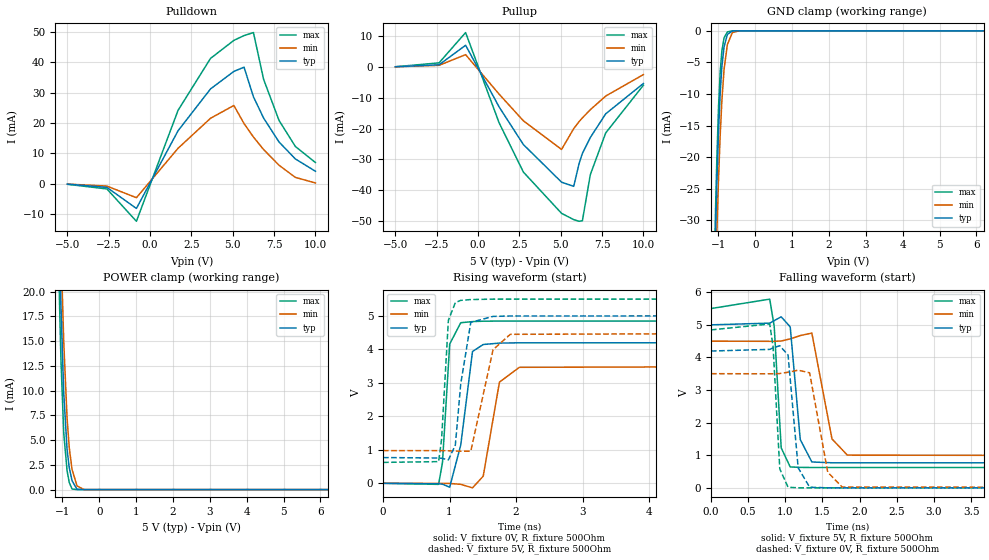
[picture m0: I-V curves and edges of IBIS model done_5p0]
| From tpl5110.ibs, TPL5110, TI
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|   Model
[Model]   done_5p0
Model_type   I/O
Polarity   Non-Inverting
Enable   Active-Low
Vinl = 1.5
Vinh = 3.5
Vmeas = 2.5
Vref = 0
Cref = 1pF
Rref = 100000
|   typ   min   max
C_comp   0.333pF   0.286pF   0.375pF
[Voltage Range]   5   4.5   5.5
[Temperature Range]   25   105   -40
[Pullup Reference]   5   4.5   5.5
[Pulldown Reference]   0   0   -0
[Power Clamp Reference]   5   4.5   5.5
[GND Clamp Reference]   0   0   0
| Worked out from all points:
|   slope of the pulldown table from 0 to 0.75 V, typ, clamps not added: 90.8 ohm
|   slope of the pullup table from 0 to 0.75 V, typ, clamps not added: 95.6 ohm
|   GND clamp passes 1 mA (typ) near -0.78 V on its own axis
|   POWER clamp passes 1 mA (typ) near -0.75 V on its own axis
|   falling waveform, V_fixture 5V, R_fixture 500Ohm: 20-80 % time 89.8ps typ, 129ps min, 67.3ps max; typ from 5 V to 0.769 V
|   rising waveform, V_fixture 0V, R_fixture 500Ohm: 20-80 % time 113ps typ, 161ps min, 80.8ps max; typ from 0 V to 4.2 V
|   rising waveform, V_fixture 5V, R_fixture 500Ohm: 20-80 % time 109ps typ, 166ps min, 75.4ps max; typ from 0.769 V to 5 V
|   falling waveform, V_fixture 0V, R_fixture 500Ohm: 20-80 % time 85.8ps typ, 127ps min, 63.1ps max; typ from 4.2 V to 0 V
[Pulldown]
|   Voltage   I(typ)   I(min)   I(max)
-5V       -132.5uA   -121.1uA   -187.6uA
-2.615V   -1.207mA   -775.6uA   -1.727mA
-830mV    -8.143mA   -4.607mA   -12.38mA
1.69V     17.46mA    11.68mA    24.19mA
3.655V    31.24mA    21.57mA    41.29mA
5.065V    37mA       25.78mA    47.23mA
5.68V     38.4mA     19.83mA    48.8mA
6.25V     28.63mA    15.37mA    49.8mA
6.865V    21.63mA    11.26mA    34.37mA
7.795V    13.76mA    6.114mA    20.88mA
8.785V    8.165mA    2.085mA    12.28mA
10V       4.104mA    252.6uA    6.983mA
[GND Clamp]
|   Voltage   I(typ)   I(min)   I(max)
-5V       -1.486A    -1.386A    -1.583A
-1.085V   -33.82mA   -41.23mA   -30.54mA
-1.07V    -30.36mA   -37.93mA   -26.82mA
-1.04V    -23.96mA   -31.7mA    -20.08mA
-995mV    -15.88mA   -23.39mA   -12mA
-950mV    -9.811mA   -16.49mA   -6.492mA
-905mV    -5.688mA   -11.08mA   -3.207mA
-845mV    -2.519mA   -6.091mA   -1.09mA
-755mV    -568.8uA   -2.164mA   -172.6uA
-620mV    -28.9uA    -276.8uA   -5.953uA
-440mV    -185.4nA   -4.113uA   -392.8nA
10V       0A         0A         0A
[Pullup]
|   Voltage   I(typ)   I(min)   I(max)
-5V       77.12uA    82.24uA    76.75uA
-2.36V    718.2uA    539.5uA    1.351mA
-755mV    7.059mA    4.014mA    11.19mA
1.27V     -12.96mA   -8.81mA    -18.11mA
2.74V     -25.2mA    -17.48mA   -34.14mA
5.05V     -37.43mA   -26.8mA    -47.56mA
5.785V    -38.78mA   -20.01mA   -49.59mA
6.115V    -31.26mA   -17.71mA   -50.14mA
6.31V     -28.07mA   -16.53mA   -49.95mA
6.79V     -22.91mA   -13.87mA   -34.97mA
7.72V     -15.21mA   -9.437mA   -21.42mA
10V       -5.357mA   -2.466mA   -5.918mA
[POWER Clamp]
|   Voltage   I(typ)   I(min)   I(max)
-5V       1.028A     955.2mA    1.095A
-1.115V   30.58mA    36.08mA    25.22mA
-1.085V   25.4mA     31.17mA    19.84mA
-1.07V    22.97mA    28.83mA    17.39mA
-1.04V    18.48mA    24.38mA    13.05mA
-965mV    9.776mA    14.94mA    5.727mA
-875mV    4.073mA    7.255mA    1.92mA
-815mV    2.212mA    4.218mA    709.2uA
-740mV    898.4uA    2.043mA    65.47uA
-605mV    31.88uA    379.8uA    154.7nA
-410mV    13.73nA    2.922uA    0A
10V       0A         0A         0A
[Ramp]
R_load = 500
|   typ   min   max
dV/dt_r   2.51801/1.12962e-10   2.10124/1.59851e-10   2.90712/8.07734e-11
dV/dt_f   2.53873/8.97966e-11   2.11357/1.2905e-10   2.92538/6.71842e-11
[Falling Waveform]
V_fixture = 5V
V_fixture_min = 4.5V
V_fixture_max = 5.5V
R_fixture = 500Ohm
C_fixture = 0F
|   Time   V(typ)   V(min)   V(max)
0s        5V         4.5V       5.5V
790.6ps   5.053V     4.495V     5.789V
850.9ps   5.129V     4.495V     4.945V
944.7ps   5.247V     4.504V     1.227V
1.066ns   4.938V     4.57V      641.2mV
1.201ns   1.482V     4.671V     628.2mV
1.357ns   794.1mV    4.748V     624.5mV
1.628ns   769.1mV    1.501V     624.5mV
1.835ns   769.1mV    1.004V     624.5mV
10ns      768.8mV    977.4mV    624.4mV
[Rising Waveform]
V_fixture = 0V
V_fixture_min = 0V
V_fixture_max = 0V
R_fixture = 500Ohm
C_fixture = 0F
|   Time   V(typ)   V(min)   V(max)
0s        -277.4nV   59.27nV    -2.215uV
835.4ps   -14.67mV   -4.246mV   -31.63mV
893.7ps   -26.66mV   -4.542mV   625.2mV
1.002ns   -115.8mV   -5.091mV   4.158V
1.168ns   1.142V     -30.39mV   4.795V
1.345ns   3.936V     -136.2mV   4.829V
1.506ns   4.145V     213.5mV    4.841V
1.75ns    4.187V     3.022V     4.845V
2.05ns    4.196V     3.464V     4.845V
10ns      4.197V     3.502V     4.845V
[Rising Waveform]
V_fixture = 5V
V_fixture_min = 4.5V
V_fixture_max = 5.5V
R_fixture = 500Ohm
C_fixture = 0F
|   Time   V(typ)   V(min)   V(max)
0s        768.8mV    977.4mV    624.4mV
835.4ps   754.6mV    976.7mV    647.2mV
879.8ps   747.5mV    976.7mV    1.308V
982.3ps   699.5mV    970.8mV    4.868V
1.087ns   1.141V     963.5mV    5.396V
1.168ns   2.966V     957.8mV    5.463V
1.319ns   4.806V     958.2mV    5.487V
1.654ns   4.984V     3.992V     5.5V
1.913ns   4.997V     4.449V     5.5V
10ns      5V         4.5V       5.5V
[Falling Waveform]
|Gnd
V_fixture = 0V
V_fixture_min = 0V
V_fixture_max = 0V
R_fixture = 500Ohm
C_fixture = 0F
|   Time   V(typ)   V(min)   V(max)
0s        4.197V     3.502V     4.845V
790.6ps   4.247V     3.499V     5.027V
835.4ps   4.294V     3.499V     4.336V
925.5ps   4.36V      3.507V     582mV
1.037ns   4.073V     3.547V     19.28mV
1.173ns   614.2mV    3.609V     1.722mV
1.327ns   20.56mV    3.529V     94.53uV
1.571ns   1.019mV    479.9mV    91.94uV
1.765ns   170.8uV    25.74mV    89.87uV
10ns      339.2nV    997.3pV    2.308uV
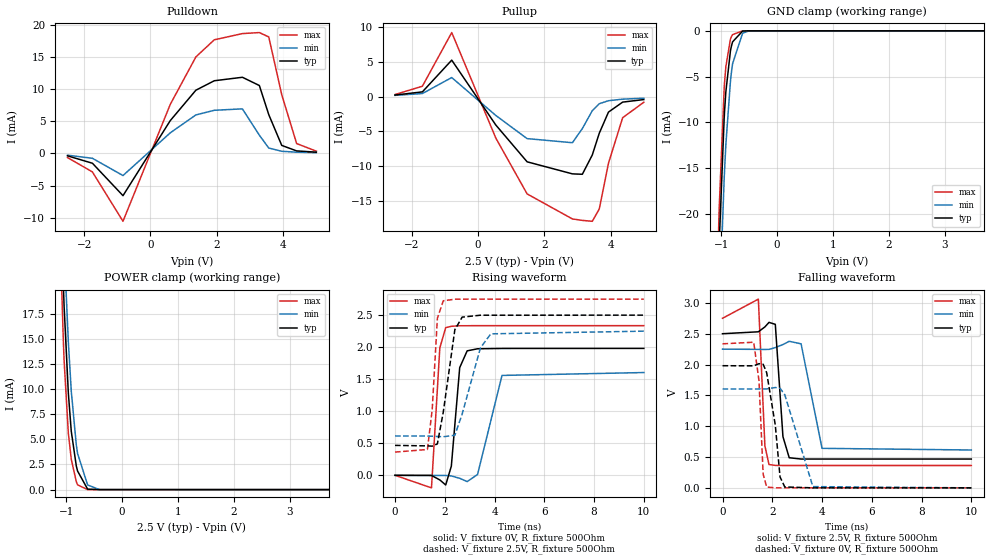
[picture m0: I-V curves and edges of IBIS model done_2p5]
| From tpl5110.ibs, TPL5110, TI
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|   Model
[Model]   done_2p5
Model_type   I/O
Polarity   Non-Inverting
Enable   Active-Low
Vinl = 0.75
Vinh = 1.75
Vmeas = 1.25
Vref = 0
Cref = 1pF
Rref = 100000
|   typ   min   max
C_comp   0.333pF   0.286pF   0.375pF
[Voltage Range]   2.5   2.25   2.75
[Temperature Range]   25   105   -40
[Pullup Reference]   2.5   2.25   2.75
[Pulldown Reference]   0   0   -0
[Power Clamp Reference]   2.5   2.25   2.75
[GND Clamp Reference]   0   0   0
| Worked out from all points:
|   slope of the pulldown table from 0 to 0.375 V, typ, clamps not added: 113 ohm
|   slope of the pullup table from 0 to 0.375 V, typ, clamps not added: 129 ohm
|   GND clamp passes 1 mA (typ) near -0.77 V on its own axis
|   POWER clamp passes 1 mA (typ) near -0.71 V on its own axis
|   falling waveform, V_fixture 2.5V, R_fixture 500Ohm: 20-80 % time 187ps typ, 310ps min, 119ps max; typ from 2.5 V to 0.467 V
|   rising waveform, V_fixture 0V, R_fixture 500Ohm: 20-80 % time 242ps typ, 394ps min, 156ps max; typ from 0 V to 1.98 V
|   rising waveform, V_fixture 2.5V, R_fixture 500Ohm: 20-80 % time 432ps typ, 693ps min, 216ps max; typ from 0.467 V to 2.5 V
|   falling waveform, V_fixture 0V, R_fixture 500Ohm: 20-80 % time 346ps typ, 608ps min, 159ps max; typ from 1.98 V to 0 V
[Pulldown]
|   Voltage   I(typ)   I(min)   I(max)
-2.5V     -377.8uA   -275.3uA   -643.7uA
-1.75V    -1.525mA   -756.3uA   -2.874mA
-827.5mV  -6.561mA   -3.438mA   -10.54mA
597.5mV   5.093mA    3.193mA    7.609mA
1.37V     9.813mA    5.974mA    14.98mA
1.925V    11.28mA    6.695mA    17.64mA
2.772V    11.82mA    6.917mA    18.6mA
3.283V    10.54mA    2.828mA    18.76mA
3.567V    6.017mA    832.4uA    18.08mA
3.958V    1.241mA    329uA      9.113mA
4.407V    388.1uA    188.4uA    1.531mA
5V        190uA      113.1uA    346.3uA
[GND Clamp]
|   Voltage   I(typ)   I(min)   I(max)
-2.5V     -532.7mA   -498.3mA   -571.1mA
-1.045V   -24.97mA   -32.7mA    -21.13mA
-1.038V   -23.46mA   -31.2mA    -19.56mA
-947.5mV  -9.534mA   -16.15mA   -6.257mA
-940mV    -8.737mA   -15.16mA   -5.592mA
-917.5mV  -6.657mA   -12.44mA   -3.935mA
-835mV    -2.176mA   -5.473mA   -895.3uA
-820mV    -1.735mA   -4.645mA   -662.1uA
-797.5mV  -1.211mA   -3.602mA   -417uA
-617.5mV  -27.18uA   -264uA     -5.53uA
-512.5mV  -1.678uA   -25.84uA   -162.4nA
5V        0A         0A         0A
[Pullup]
|   Voltage   I(typ)   I(min)   I(max)
-2.5V     224.1uA    179.4uA    297.8uA
-1.675V   681.7uA    439.6uA    1.497mA
-790mV    5.257mA    2.749mA    9.233mA
537.5mV   -4.091mA   -2.715mA   -5.969mA
1.482V    -9.403mA   -6.059mA   -14.03mA
2.848V    -11.14mA   -6.648mA   -17.64mA
3.147V    -11.2mA    -4.612mA   -17.85mA
3.447V    -8.416mA   -2.03mA    -17.98mA
3.658V    -5.27mA    -1.025mA   -16.2mA
3.935V    -2.234mA   -592.6uA   -9.605mA
4.362V    -795.1uA   -368.9uA   -3.043mA
5V        -428.1uA   -232uA     -814.8uA
[POWER Clamp]
|   Voltage   I(typ)   I(min)   I(max)
-2.5V     372.4mA    347.3mA    397mA
-1.143V   35.73mA    40.86mA    30.73mA
-1.052V   20.35mA    26.24mA    14.83mA
-1.045V   19.26mA    25.14mA    13.78mA
-1.038V   18.19mA    24.07mA    12.79mA
-962.5mV  9.598mA    14.7mA     5.607mA
-910mV    5.801mA    9.789mA    3.024mA
-820mV    2.351mA    4.44mA     793.4uA
-797.5mV  1.849mA    3.597mA    473.7uA
-617.5mV  49.01uA    467.4uA    281.4nA
-407.5mV  17.43nA    2.726uA    0A
5V        0A         0A         0A
[Ramp]
R_load = 500
|   typ   min   max
dV/dt_r   1.18847/2.40138e-10   0.962378/3.92229e-10   1.40149/1.56158e-10
dV/dt_f   1.21976/1.86873e-10   0.981537/3.10165e-10   1.43248/1.19215e-10
[Falling Waveform]
V_fixture = 2.5V
V_fixture_min = 2.25V
V_fixture_max = 2.75V
R_fixture = 500Ohm
C_fixture = 0F
|   Time   V(typ)   V(min)   V(max)
0s        2.5V       2.25V      2.75V
1.441ns   2.531V     2.246V     3.061V
1.703ns   2.61V      2.245V     682mV
1.869ns   2.684V     2.246V     378.7mV
2.122ns   2.652V     2.275V     364mV
2.429ns   830.3mV    2.324V     362.7mV
2.681ns   488.6mV    2.377V     362.7mV
3.158ns   467.4mV    2.336V     362.7mV
4ns       467.4mV    640.9mV    362.7mV
10ns      467.1mV    614.1mV    362.5mV
[Rising Waveform]
V_fixture = 0V
V_fixture_min = 0V
V_fixture_max = 0V
R_fixture = 500Ohm
C_fixture = 0F
|   Time   V(typ)   V(min)   V(max)
0s        -129.9nV   27.63nV    -30.88nV
1.466ns   -2.084mV   -1.516mV   -195.8mV
1.801ns   -71.96mV   -1.861mV   1.989V
2.037ns   -151mV     -2.105mV   2.305V
2.264ns   143.4mV    -9.781mV   2.326V
2.6ns     1.681V     -46.57mV   2.335V
2.9ns     1.943V     -97.85mV   2.335V
3.317ns   1.975V     12.64mV    2.336V
4.3ns     1.98V      1.559V     2.336V
10ns      1.981V     1.604V     2.336V
[Rising Waveform]
V_fixture = 2.5V
V_fixture_min = 2.25V
V_fixture_max = 2.75V
R_fixture = 500Ohm
C_fixture = 0F
|   Time   V(typ)   V(min)   V(max)
0s        467.1mV    614.1mV    362.5mV
1.302ns   459.4mV    613.5mV    403.3mV
1.495ns   455.4mV    610.1mV    1.024V
1.703ns   490.6mV    606.2mV    2.452V
1.941ns   988.9mV    601.6mV    2.724V
2.405ns   2.273V     625.8mV    2.749V
2.699ns   2.469V     955.9mV    2.749V
3.432ns   2.499V     1.988V     2.75V
3.849ns   2.499V     2.208V     2.75V
10ns      2.5V       2.25V      2.75V
[Falling Waveform]
|Gnd
V_fixture = 0V
V_fixture_min = 0V
V_fixture_max = 0V
R_fixture = 500Ohm
C_fixture = 0F
|   Time   V(typ)   V(min)   V(max)
0s        1.981V     1.604V     2.336V
1.254ns   1.979V     1.604V     2.362V
1.466ns   2.014V     1.604V     1.739V
1.633ns   2.005V     1.604V     223.4mV
1.775ns   1.868V     1.605V     12.98mV
2.122ns   1.016V     1.627V     138.2uV
2.312ns   176.9mV    1.616V     134.9uV
2.503ns   14.7mV     1.51V      131.5uV
3.632ns   311.5uV    20.15mV    111.7uV
10ns      150.1nV    26.68nV    56.7nV
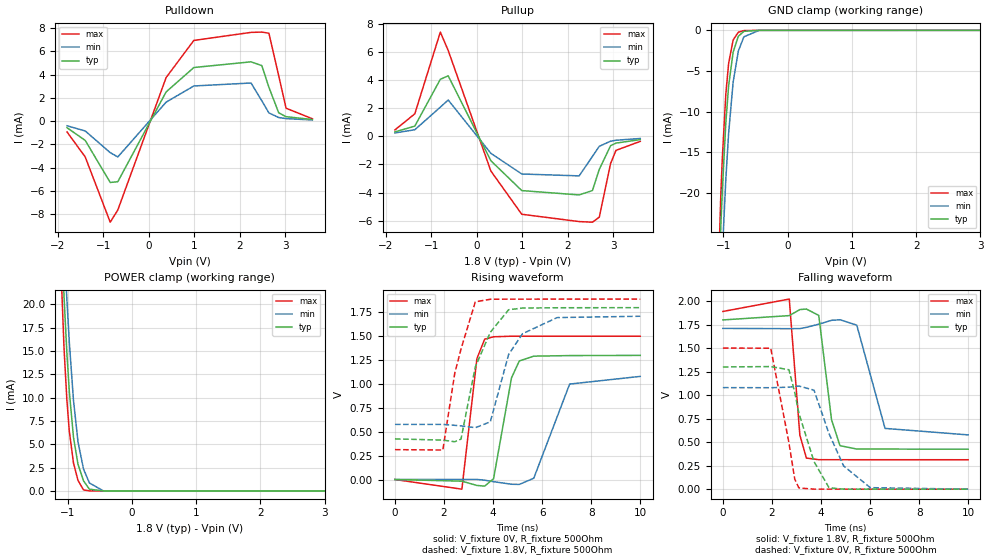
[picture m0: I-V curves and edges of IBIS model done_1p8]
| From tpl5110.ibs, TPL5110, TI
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|   Model
[Model]   done_1p8
Model_type   I/O
Polarity   Non-Inverting
Enable   Active-Low
Vinl = 0.54
Vinh = 1.26
Vmeas = 0.9
Vref = 0
Cref = 1pF
Rref = 100000
|   typ   min   max
C_comp   0.333pF   0.286pF   0.375pF
[Voltage Range]   1.8   1.71   1.89
[Temperature Range]   25   105   -40
[Pullup Reference]   1.8   1.71   1.89
[Pulldown Reference]   0   -0   0
[Power Clamp Reference]   1.8   1.71   1.89
[GND Clamp Reference]   0   0   0
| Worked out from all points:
|   slope of the pulldown table from 0 to 0.27 V, typ, clamps not added: 146 ohm
|   slope of the pullup table from 0 to 0.27 V, typ, clamps not added: 177 ohm
|   GND clamp passes 1 mA (typ) near -0.78 V on its own axis
|   POWER clamp passes 1 mA (typ) near -0.75 V on its own axis
|   falling waveform, V_fixture 1.8V, R_fixture 500Ohm: 20-80 % time 367ps typ, 577ps min, 233ps max; typ from 1.8 V to 0.425 V
|   rising waveform, V_fixture 0V, R_fixture 500Ohm: 20-80 % time 510ps typ, 810ps min, 326ps max; typ from 0 V to 1.3 V
|   rising waveform, V_fixture 1.8V, R_fixture 500Ohm: 20-80 % time 870ps typ, 875ps min, 698ps max; typ from 0.425 V to 1.8 V
|   falling waveform, V_fixture 0V, R_fixture 500Ohm: 20-80 % time 898ps typ, 1.02ns min, 646ps max; typ from 1.3 V to 0 V
[Pulldown]
|   Voltage   I(typ)   I(min)   I(max)
-1.8V     -571.7uA   -401.9uA   -935.3uA
-1.4V     -1.662mA   -848.3uA   -3.082mA
-849.6mV  -5.278mA   -2.713mA   -8.695mA
-682.2mV  -5.211mA   -3.084mA   -7.646mA
381.6mV   2.511mA    1.632mA    3.748mA
991.8mV   4.608mA    3.02mA     6.936mA
2.25V     5.096mA    3.276mA    7.628mA
2.488V    4.771mA    1.743mA    7.654mA
2.644V    2.903mA    702.6uA    7.553mA
2.86V     709.1uA    307uA      3.893mA
3.022V    379.5uA    212.4uA    1.106mA
3.6V      134.8uA    96.99uA    200.5uA
[GND Clamp]
|   Voltage   I(typ)   I(min)   I(max)
-1.8V     -271.2mA   -257.5mA   -290.2mA
-1.152V   -51.07mA   -57.26mA   -49.44mA
-1.044V   -24.77mA   -32.5mA    -20.92mA
-1.039V   -23.68mA   -31.42mA   -19.79mA
-1.017V   -19.58mA   -27.29mA   -15.63mA
-963mV    -11.35mA   -18.33mA   -7.83mA
-919.8mV  -6.849mA   -12.7mA    -4.083mA
-849.6mV  -2.692mA   -6.394mA   -1.191mA
-768.6mV  -733.1uA   -2.559mA   -229.2uA
-682.2mV  -124.3uA   -797.2uA   -33.36uA
-444.6mV  -228.1nA   -4.653uA   -6.695nA
3.6V      0A         0A         0A
[Pullup]
|   Voltage   I(typ)   I(min)   I(max)
-1.8V     312.5uA    239.1uA    452.5uA
-1.363V   722.9uA    463.9uA    1.598mA
-801mV    4.054mA    2.072mA    7.411mA
-628.2mV  4.299mA    2.58mA     6.106mA
311.4mV   -1.74mA    -1.214mA   -2.472mA
991.8mV   -3.863mA   -2.683mA   -5.547mA
2.255V    -4.172mA   -2.817mA   -6.067mA
2.547V    -3.86mA    -1.435mA   -6.111mA
2.698V    -2.355mA   -712uA     -5.751mA
2.947V    -668.2uA   -348.3uA   -1.938mA
3.065V    -486.1uA   -282.3uA   -1.004mA
3.6V      -239.1uA   -156.9uA   -361.3uA
[POWER Clamp]
|   Voltage   I(typ)   I(min)   I(max)
-1.8V     191.1mA    181.5mA    201.1mA
-1.147V   36.53mA    41.59mA    31.6mA
-1.06V    21.53mA    27.4mA     15.98mA
-1.055V   20.71mA    26.59mA    15.19mA
-1.012V   14.81mA    20.56mA    9.762mA
-973.8mV  10.66mA    15.95mA    6.401mA
-909mV    5.756mA    9.717mA    2.998mA
-838.8mV  2.861mA    5.282mA    1.129mA
-752.4mV  1.079mA    2.331mA    108.5uA
-660.6mV  184.8uA    854.2uA    1.928uA
-444.6mV  88.96nA    7.913uA    0A
3.6V      0A         0A         0A
[Ramp]
R_load = 500
|   typ   min   max
dV/dt_r   0.77995/5.0775e-10   0.647775/8.10097e-10   0.900734/3.25085e-10
dV/dt_f   0.824711/3.67483e-10   0.679625/5.72303e-10   0.946245/2.33074e-10
[Falling Waveform]
V_fixture = 1.8V
V_fixture_min = 1.71V
V_fixture_max = 1.89V
R_fixture = 500Ohm
C_fixture = 0F
|   Time   V(typ)   V(min)   V(max)
0s        1.8V       1.71V      1.89V
2.707ns   1.846V     1.707V     2.022V
3.138ns   1.91V      1.708V     575.4mV
3.404ns   1.916V     1.721V     330.9mV
3.909ns   1.848V     1.755V     313.5mV
4.43ns    738.3mV    1.796V     313.2mV
4.774ns   463mV      1.802V     313.2mV
5.458ns   426.6mV    1.745V     313.1mV
6.611ns   426.3mV    646.2mV    313.1mV
10ns      425.5mV    577.3mV    312.9mV
[Rising Waveform]
V_fixture = 0V
V_fixture_min = 0V
V_fixture_max = 0V
R_fixture = 500Ohm
C_fixture = 0F
|   Time   V(typ)   V(min)   V(max)
0s        48.06nV    21.41nV    12.41nV
2.728ns   -17.51mV   622uV      -101.2mV
3.341ns   -62.31mV   761.7uV    1.266V
3.658ns   -68.96mV   -7.249mV   1.47V
4.02ns    7.948mV    -22.77mV   1.495V
4.751ns   1.064V     -49.7mV    1.501V
5.069ns   1.242V     -51.44mV   1.501V
5.659ns   1.292V     13.36mV    1.501V
7.121ns   1.298V     999.6mV    1.501V
10ns      1.3V       1.08V      1.501V
[Rising Waveform]
V_fixture = 1.8V
V_fixture_min = 1.71V
V_fixture_max = 1.89V
R_fixture = 500Ohm
C_fixture = 0F
|   Time   V(typ)   V(min)   V(max)
0s        425.5mV    577.3mV    312.9mV
1.952ns   412.6mV    577.1mV    308.8mV
2.437ns   395.6mV    567.5mV    1.112V
2.692ns   423.1mV    562mV      1.366V
3.276ns   1.18V      542.7mV    1.861V
3.888ns   1.542V     604.2mV    1.888V
4.633ns   1.778V     1.309V     1.889V
5.201ns   1.796V     1.527V     1.889V
6.611ns   1.799V     1.696V     1.89V
10ns      1.8V       1.71V      1.89V
[Falling Waveform]
|Gnd
V_fixture = 0V
V_fixture_min = 0V
V_fixture_max = 0V
R_fixture = 500Ohm
C_fixture = 0F
|   Time   V(typ)   V(min)   V(max)
0s        1.3V       1.08V      1.501V
1.952ns   1.304V     1.079V     1.499V
2.692ns   1.27V      1.085V     495.1mV
2.929ns   1.029V     1.091V     107.1mV
3.1ns     805.9mV    1.097V     12.77mV
3.716ns   293.3mV    1.053V     254.4uV
4.328ns   14.77mV    589.6mV    229.6uV
4.923ns   509.8uV    247.2mV    205.5uV
6.009ns   400.8uV    16.1mV     161.5uV
10ns      49.17nV    102.8nV    1.672nV
